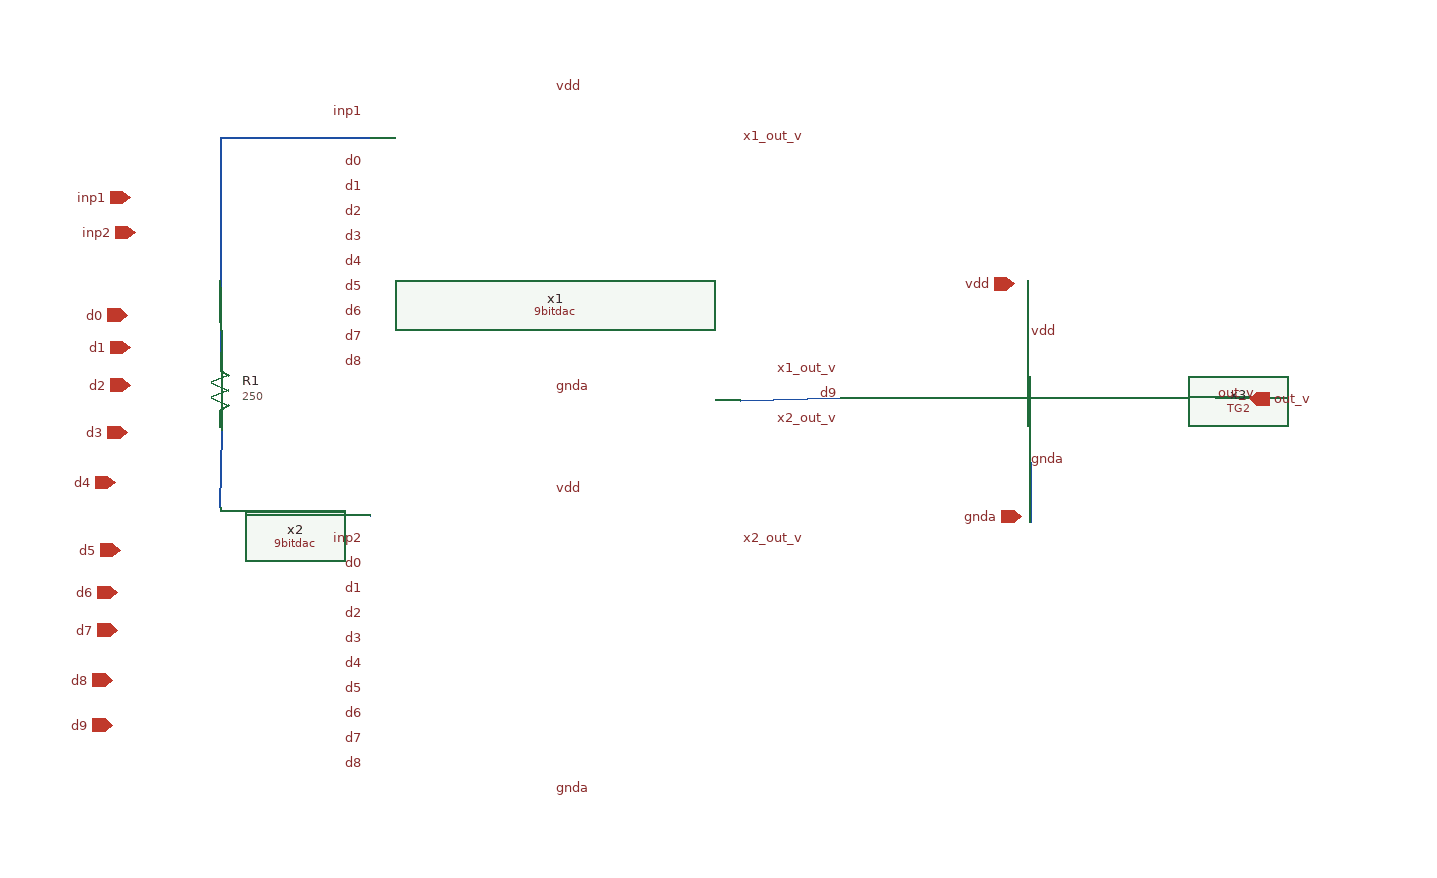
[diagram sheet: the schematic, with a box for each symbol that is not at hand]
v {xschem version=2.9.9 file_version=1.2 }
G {}
K {}
V {}
S {}
E {}
N -36 -654 -36 -610 { lab=vdd}
N -34 -508 -34 -460 { lab=#net1}
N 114 -560 152 -560 { lab=#net2}
N -266 -558 -186 -560 { lab=#net3}
N -682 -640 -682 -596 { lab=#net4}
N -682 -648 -682 -620 { lab=#net4}
N -682 -472 -680 -534 { lab=#net5}
N -682 -470 -562 -466 { lab=#net6}
N -682 -768 -562 -768 { lab=#net4}
N -682 -768 -682 -646 { lab=#net4}
C {ipin.sym} -754 -720 0 0 {name=p1 lab=inp1}
C {ipin.sym} -750 -692 0 0 {name=p2 lab=inp2
}
C {iopin.sym} -46.5 -651 0 0 {name=p6 lab=vdd}
C {iopin.sym} -40.5 -465 0 0 {name=p7 lab=gnda}
C {res.sym} -682 -566 0 0 {name=R1
value=250
footprint=1206
device=resistor
m=1}
C {/home/harshitha/Desktop/xschem/xschem_library/TG2.sym} -36 -492 0 0 {name=x3}
C {devices/lab_wire.sym} -186 -582 0 0 {name=p20 lab=x1_out_v}
C {devices/lab_wire.sym} -36 -612 0 1 {name=p21 lab=vdd}
C {devices/lab_wire.sym} 114 -562 0 1 {name=p22 lab=out_v}
C {devices/lab_wire.sym} -36 -509.5 0 1 {name=p24 lab=gnda}
C {devices/lab_wire.sym} -186 -542 0 0 {name=p25 lab=x2_out_v}
C {ipin.sym} -756 -626 0 0 {name=p3 lab=d0}
C {ipin.sym} -754 -600 0 0 {name=p11 lab=d1}
C {opin.sym} 141.5 -559 0 0 {name=p17 lab=out_v}
C {devices/lab_wire.sym} -186 -562 0 0 {name=p28 lab=d9}
C {ipin.sym} -754 -570 0 0 {name=p19 lab=d2}
C {ipin.sym} -756 -532 0 0 {name=p34 lab=d3}
C {ipin.sym} -766 -492 0 0 {name=p4 lab=d4}
C {ipin.sym} -762 -438 0 0 {name=p5 lab=d5}
C {ipin.sym} -764 -404 0 0 {name=p27 lab=d6}
C {ipin.sym} -764 -374 0 0 {name=p9 lab=d7}
C {ipin.sym} -768 -334 0 0 {name=p10 lab=d8}
C {/home/harshitha/Desktop/xschem/xschem_library/9bitdac.sym} -416 -682 0 0 {name=x1}
C {/home/harshitha/Desktop/xschem/xschem_library/9bitdac.sym} -416 -360 0 0 {name=x2}
C {devices/lab_pin.sym} -566 -788 0 0 {name=p8 lab=inp1}
C {devices/lab_pin.sym} -416 -808 0 1 {name=p12 lab=vdd}
C {devices/lab_pin.sym} -566 -748 0 0 {name=p13 lab=d0}
C {devices/lab_pin.sym} -566 -728 0 0 {name=p14 lab=d1}
C {devices/lab_pin.sym} -566 -708 0 0 {name=p15 lab=d2}
C {devices/lab_pin.sym} -266 -768 0 1 {name=p16 lab=x1_out_v}
C {devices/lab_pin.sym} -566 -688 0 0 {name=p18 lab=d3}
C {devices/lab_pin.sym} -566 -668 0 0 {name=p23 lab=d4}
C {devices/lab_pin.sym} -416 -568 0 1 {name=p26 lab=gnda}
C {devices/lab_pin.sym} -566 -648 0 0 {name=p29 lab=d5}
C {devices/lab_pin.sym} -566 -628 0 0 {name=p30 lab=d6}
C {devices/lab_pin.sym} -566 -608 0 0 {name=p31 lab=d7}
C {devices/lab_pin.sym} -566 -588 0 0 {name=p32 lab=d8}
C {devices/lab_pin.sym} -566 -446 0 0 {name=p35 lab=inp2}
C {devices/lab_pin.sym} -416 -486 0 1 {name=p36 lab=vdd}
C {devices/lab_pin.sym} -566 -426 0 0 {name=p37 lab=d0}
C {devices/lab_pin.sym} -566 -406 0 0 {name=p38 lab=d1}
C {devices/lab_pin.sym} -566 -386 0 0 {name=p39 lab=d2}
C {devices/lab_pin.sym} -266 -446 0 1 {name=p40 lab=x2_out_v}
C {devices/lab_pin.sym} -566 -366 0 0 {name=p41 lab=d3}
C {devices/lab_pin.sym} -566 -346 0 0 {name=p42 lab=d4}
C {devices/lab_pin.sym} -416 -246 0 1 {name=p43 lab=gnda}
C {devices/lab_pin.sym} -566 -326 0 0 {name=p44 lab=d5}
C {devices/lab_pin.sym} -566 -306 0 0 {name=p45 lab=d6}
C {devices/lab_pin.sym} -566 -286 0 0 {name=p46 lab=d7}
C {devices/lab_pin.sym} -566 -266 0 0 {name=p47 lab=d8}
C {ipin.sym} -768 -298 0 0 {name=p33 lab=d9}
